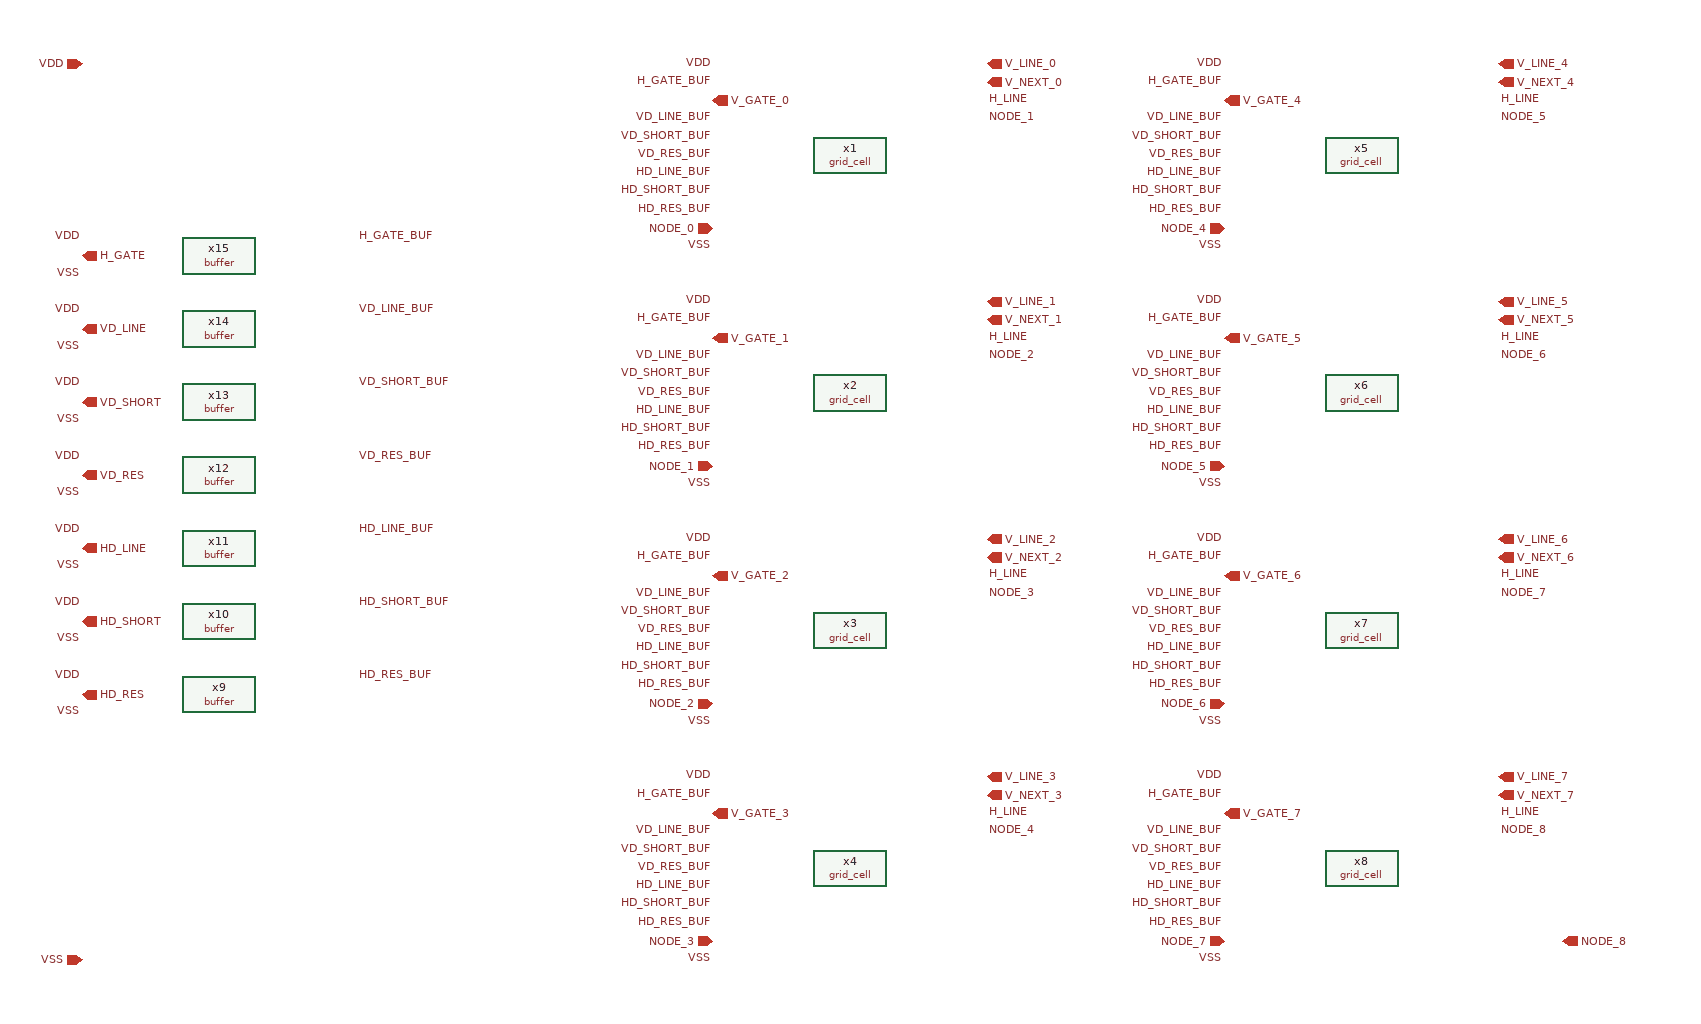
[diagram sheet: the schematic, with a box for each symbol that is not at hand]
v {xschem version=3.4.5 file_version=1.2
}
G {}
K {}
V {}
S {}
E {}
C {grid_cell.sym} 1120 -1040 0 0 {name=x1}
C {devices/lab_pin.sym} 970 -940 0 0 {name=p1 sig_type=std_logic lab=VSS}
C {devices/lab_pin.sym} 970 -1140 0 0 {name=p2 sig_type=std_logic lab=VDD}
C {devices/iopin.sym} 280 -160 2 0 {name=p7 lab=VSS}
C {devices/iopin.sym} 280 -1140 2 0 {name=p3 lab=VDD}
C {devices/iopin.sym} 970 -960 2 0 {name=p4 lab=NODE_0}
C {devices/ipin.sym} 280 -450 2 1 {name=p5 lab=HD_RES}
C {devices/ipin.sym} 280 -530 2 1 {name=p6 lab=HD_SHORT}
C {devices/ipin.sym} 280 -610 2 1 {name=p8 lab=HD_LINE}
C {buffer.sym} 430 -450 0 0 {name=x9}
C {buffer.sym} 430 -530 0 0 {name=x10}
C {buffer.sym} 430 -610 0 0 {name=x11}
C {devices/lab_pin.sym} 280 -430 0 0 {name=p24 sig_type=std_logic lab=VSS}
C {devices/lab_pin.sym} 280 -510 0 0 {name=p25 sig_type=std_logic lab=VSS}
C {devices/lab_pin.sym} 280 -590 0 0 {name=p26 sig_type=std_logic lab=VSS}
C {devices/lab_pin.sym} 280 -470 0 0 {name=p28 sig_type=std_logic lab=VDD}
C {devices/lab_pin.sym} 280 -550 0 0 {name=p29 sig_type=std_logic lab=VDD}
C {devices/lab_pin.sym} 280 -630 0 0 {name=p30 sig_type=std_logic lab=VDD}
C {devices/lab_pin.sym} 970 -980 0 0 {name=p36 sig_type=std_logic lab=HD_RES_BUF}
C {devices/lab_pin.sym} 970 -1000 0 0 {name=p37 sig_type=std_logic lab=HD_SHORT_BUF}
C {devices/lab_pin.sym} 970 -1020 0 0 {name=p38 sig_type=std_logic lab=HD_LINE_BUF}
C {devices/ipin.sym} 970 -1100 2 1 {name=p41 lab=V_GATE_0}
C {devices/lab_pin.sym} 970 -1120 0 0 {name=p42 sig_type=std_logic lab=H_GATE_BUF}
C {devices/iopin.sym} 1270 -1140 2 1 {name=p43 lab=V_LINE_0}
C {devices/iopin.sym} 1270 -1120 2 1 {name=p44 lab=V_NEXT_0}
C {devices/lab_pin.sym} 1270 -1100 0 1 {name=p45 sig_type=std_logic lab=H_LINE}
C {devices/lab_pin.sym} 1270 -1080 0 1 {name=p46 sig_type=std_logic lab=NODE_1}
C {grid_cell.sym} 1120 -780 0 0 {name=x2}
C {devices/lab_pin.sym} 970 -680 0 0 {name=p10 sig_type=std_logic lab=VSS}
C {devices/lab_pin.sym} 970 -880 0 0 {name=p11 sig_type=std_logic lab=VDD}
C {devices/lab_pin.sym} 970 -720 0 0 {name=p14 sig_type=std_logic lab=HD_RES_BUF}
C {devices/lab_pin.sym} 970 -740 0 0 {name=p15 sig_type=std_logic lab=HD_SHORT_BUF}
C {devices/lab_pin.sym} 970 -760 0 0 {name=p16 sig_type=std_logic lab=HD_LINE_BUF}
C {devices/ipin.sym} 970 -840 2 1 {name=p19 lab=V_GATE_1}
C {devices/lab_pin.sym} 970 -860 0 0 {name=p20 sig_type=std_logic lab=H_GATE_BUF}
C {devices/iopin.sym} 1270 -880 2 1 {name=p21 lab=V_LINE_1}
C {devices/iopin.sym} 1270 -860 2 1 {name=p22 lab=V_NEXT_1}
C {devices/lab_pin.sym} 1270 -840 0 1 {name=p23 sig_type=std_logic lab=H_LINE}
C {devices/lab_pin.sym} 1270 -820 0 1 {name=p33 sig_type=std_logic lab=NODE_2}
C {grid_cell.sym} 1120 -520 0 0 {name=x3}
C {devices/lab_pin.sym} 970 -420 0 0 {name=p34 sig_type=std_logic lab=VSS}
C {devices/lab_pin.sym} 970 -620 0 0 {name=p47 sig_type=std_logic lab=VDD}
C {devices/lab_pin.sym} 970 -460 0 0 {name=p50 sig_type=std_logic lab=HD_RES_BUF}
C {devices/lab_pin.sym} 970 -480 0 0 {name=p51 sig_type=std_logic lab=HD_SHORT_BUF}
C {devices/lab_pin.sym} 970 -500 0 0 {name=p52 sig_type=std_logic lab=HD_LINE_BUF}
C {devices/ipin.sym} 970 -580 2 1 {name=p55 lab=V_GATE_2}
C {devices/lab_pin.sym} 970 -600 0 0 {name=p56 sig_type=std_logic lab=H_GATE_BUF}
C {devices/iopin.sym} 1270 -620 2 1 {name=p57 lab=V_LINE_2}
C {devices/iopin.sym} 1270 -600 2 1 {name=p58 lab=V_NEXT_2}
C {devices/lab_pin.sym} 1270 -580 0 1 {name=p59 sig_type=std_logic lab=H_LINE}
C {devices/lab_pin.sym} 1270 -560 0 1 {name=p60 sig_type=std_logic lab=NODE_3}
C {grid_cell.sym} 1120 -260 0 0 {name=x4}
C {devices/lab_pin.sym} 970 -160 0 0 {name=p61 sig_type=std_logic lab=VSS}
C {devices/lab_pin.sym} 970 -360 0 0 {name=p62 sig_type=std_logic lab=VDD}
C {devices/lab_pin.sym} 970 -200 0 0 {name=p65 sig_type=std_logic lab=HD_RES_BUF}
C {devices/lab_pin.sym} 970 -220 0 0 {name=p66 sig_type=std_logic lab=HD_SHORT_BUF}
C {devices/lab_pin.sym} 970 -240 0 0 {name=p67 sig_type=std_logic lab=HD_LINE_BUF}
C {devices/ipin.sym} 970 -320 2 1 {name=p70 lab=V_GATE_3}
C {devices/lab_pin.sym} 970 -340 0 0 {name=p71 sig_type=std_logic lab=H_GATE_BUF}
C {devices/iopin.sym} 1270 -360 2 1 {name=p72 lab=V_LINE_3}
C {devices/iopin.sym} 1270 -340 2 1 {name=p73 lab=V_NEXT_3}
C {devices/lab_pin.sym} 1270 -320 0 1 {name=p74 sig_type=std_logic lab=H_LINE}
C {devices/lab_pin.sym} 1270 -300 0 1 {name=p75 sig_type=std_logic lab=NODE_4}
C {grid_cell.sym} 1680 -1040 0 0 {name=x5}
C {devices/lab_pin.sym} 1530 -940 0 0 {name=p76 sig_type=std_logic lab=VSS}
C {devices/lab_pin.sym} 1530 -1140 0 0 {name=p77 sig_type=std_logic lab=VDD}
C {devices/lab_pin.sym} 1530 -980 0 0 {name=p80 sig_type=std_logic lab=HD_RES_BUF}
C {devices/lab_pin.sym} 1530 -1000 0 0 {name=p81 sig_type=std_logic lab=HD_SHORT_BUF}
C {devices/lab_pin.sym} 1530 -1020 0 0 {name=p82 sig_type=std_logic lab=HD_LINE_BUF}
C {devices/ipin.sym} 1530 -1100 2 1 {name=p85 lab=V_GATE_4}
C {devices/lab_pin.sym} 1530 -1120 0 0 {name=p86 sig_type=std_logic lab=H_GATE_BUF}
C {devices/iopin.sym} 1830 -1140 2 1 {name=p87 lab=V_LINE_4}
C {devices/iopin.sym} 1830 -1120 2 1 {name=p88 lab=V_NEXT_4}
C {devices/lab_pin.sym} 1830 -1100 0 1 {name=p89 sig_type=std_logic lab=H_LINE}
C {devices/lab_pin.sym} 1830 -1080 0 1 {name=p90 sig_type=std_logic lab=NODE_5}
C {grid_cell.sym} 1680 -780 0 0 {name=x6}
C {devices/lab_pin.sym} 1530 -680 0 0 {name=p91 sig_type=std_logic lab=VSS}
C {devices/lab_pin.sym} 1530 -880 0 0 {name=p92 sig_type=std_logic lab=VDD}
C {devices/lab_pin.sym} 1530 -720 0 0 {name=p95 sig_type=std_logic lab=HD_RES_BUF}
C {devices/lab_pin.sym} 1530 -740 0 0 {name=p96 sig_type=std_logic lab=HD_SHORT_BUF}
C {devices/lab_pin.sym} 1530 -760 0 0 {name=p97 sig_type=std_logic lab=HD_LINE_BUF}
C {devices/ipin.sym} 1530 -840 2 1 {name=p100 lab=V_GATE_5}
C {devices/lab_pin.sym} 1530 -860 0 0 {name=p101 sig_type=std_logic lab=H_GATE_BUF}
C {devices/iopin.sym} 1830 -880 2 1 {name=p102 lab=V_LINE_5}
C {devices/iopin.sym} 1830 -860 2 1 {name=p103 lab=V_NEXT_5}
C {devices/lab_pin.sym} 1830 -840 0 1 {name=p104 sig_type=std_logic lab=H_LINE}
C {devices/lab_pin.sym} 1830 -820 0 1 {name=p105 sig_type=std_logic lab=NODE_6}
C {grid_cell.sym} 1680 -520 0 0 {name=x7}
C {devices/lab_pin.sym} 1530 -420 0 0 {name=p106 sig_type=std_logic lab=VSS}
C {devices/lab_pin.sym} 1530 -620 0 0 {name=p107 sig_type=std_logic lab=VDD}
C {devices/lab_pin.sym} 1530 -460 0 0 {name=p110 sig_type=std_logic lab=HD_RES_BUF}
C {devices/lab_pin.sym} 1530 -480 0 0 {name=p111 sig_type=std_logic lab=HD_SHORT_BUF}
C {devices/lab_pin.sym} 1530 -500 0 0 {name=p112 sig_type=std_logic lab=HD_LINE_BUF}
C {devices/ipin.sym} 1530 -580 2 1 {name=p115 lab=V_GATE_6}
C {devices/lab_pin.sym} 1530 -600 0 0 {name=p116 sig_type=std_logic lab=H_GATE_BUF}
C {devices/iopin.sym} 1830 -620 2 1 {name=p117 lab=V_LINE_6}
C {devices/iopin.sym} 1830 -600 2 1 {name=p118 lab=V_NEXT_6}
C {devices/lab_pin.sym} 1830 -580 0 1 {name=p119 sig_type=std_logic lab=H_LINE}
C {devices/lab_pin.sym} 1830 -560 0 1 {name=p120 sig_type=std_logic lab=NODE_7}
C {grid_cell.sym} 1680 -260 0 0 {name=x8}
C {devices/lab_pin.sym} 1530 -160 0 0 {name=p121 sig_type=std_logic lab=VSS}
C {devices/lab_pin.sym} 1530 -360 0 0 {name=p122 sig_type=std_logic lab=VDD}
C {devices/lab_pin.sym} 1530 -200 0 0 {name=p125 sig_type=std_logic lab=HD_RES_BUF}
C {devices/lab_pin.sym} 1530 -220 0 0 {name=p126 sig_type=std_logic lab=HD_SHORT_BUF}
C {devices/lab_pin.sym} 1530 -240 0 0 {name=p127 sig_type=std_logic lab=HD_LINE_BUF}
C {devices/ipin.sym} 1530 -320 2 1 {name=p130 lab=V_GATE_7}
C {devices/lab_pin.sym} 1530 -340 0 0 {name=p131 sig_type=std_logic lab=H_GATE_BUF}
C {devices/iopin.sym} 1830 -360 2 1 {name=p132 lab=V_LINE_7}
C {devices/iopin.sym} 1830 -340 2 1 {name=p133 lab=V_NEXT_7}
C {devices/lab_pin.sym} 1830 -320 0 1 {name=p134 sig_type=std_logic lab=H_LINE}
C {devices/lab_pin.sym} 1830 -300 0 1 {name=p135 sig_type=std_logic lab=NODE_8}
C {devices/lab_pin.sym} 580 -630 0 1 {name=p137 sig_type=std_logic lab=HD_LINE_BUF}
C {devices/lab_pin.sym} 580 -550 0 1 {name=p138 sig_type=std_logic lab=HD_SHORT_BUF}
C {devices/lab_pin.sym} 580 -470 0 1 {name=p139 sig_type=std_logic lab=HD_RES_BUF}
C {devices/iopin.sym} 1900 -180 2 1 {name=p140 lab=NODE_8}
C {devices/iopin.sym} 970 -700 2 0 {name=p13 lab=NODE_1}
C {devices/iopin.sym} 970 -440 2 0 {name=p35 lab=NODE_2}
C {devices/iopin.sym} 970 -180 2 0 {name=p49 lab=NODE_3}
C {devices/iopin.sym} 1530 -960 2 0 {name=p64 lab=NODE_4}
C {devices/iopin.sym} 1530 -700 2 0 {name=p79 lab=NODE_5}
C {devices/iopin.sym} 1530 -440 2 0 {name=p94 lab=NODE_6}
C {devices/iopin.sym} 1530 -180 2 0 {name=p109 lab=NODE_7}
C {devices/ipin.sym} 280 -690 2 1 {name=p9 lab=VD_RES}
C {devices/ipin.sym} 280 -770 2 1 {name=p27 lab=VD_SHORT}
C {devices/ipin.sym} 280 -850 2 1 {name=p31 lab=VD_LINE}
C {buffer.sym} 430 -690 0 0 {name=x12}
C {buffer.sym} 430 -770 0 0 {name=x13}
C {buffer.sym} 430 -850 0 0 {name=x14}
C {devices/lab_pin.sym} 280 -670 0 0 {name=p124 sig_type=std_logic lab=VSS}
C {devices/lab_pin.sym} 280 -750 0 0 {name=p136 sig_type=std_logic lab=VSS}
C {devices/lab_pin.sym} 280 -830 0 0 {name=p141 sig_type=std_logic lab=VSS}
C {devices/lab_pin.sym} 280 -710 0 0 {name=p142 sig_type=std_logic lab=VDD}
C {devices/lab_pin.sym} 280 -790 0 0 {name=p143 sig_type=std_logic lab=VDD}
C {devices/lab_pin.sym} 280 -870 0 0 {name=p144 sig_type=std_logic lab=VDD}
C {devices/lab_pin.sym} 580 -870 0 1 {name=p145 sig_type=std_logic lab=VD_LINE_BUF
}
C {devices/lab_pin.sym} 580 -790 0 1 {name=p146 sig_type=std_logic lab=VD_SHORT_BUF}
C {devices/lab_pin.sym} 580 -710 0 1 {name=p147 sig_type=std_logic lab=VD_RES_BUF}
C {devices/ipin.sym} 280 -930 2 1 {name=p148 lab=H_GATE}
C {buffer.sym} 430 -930 0 0 {name=x15}
C {devices/lab_pin.sym} 280 -910 0 0 {name=p149 sig_type=std_logic lab=VSS}
C {devices/lab_pin.sym} 280 -950 0 0 {name=p150 sig_type=std_logic lab=VDD}
C {devices/lab_pin.sym} 580 -950 0 1 {name=p151 sig_type=std_logic lab=H_GATE_BUF}
C {devices/lab_pin.sym} 970 -1080 0 0 {name=p12 sig_type=std_logic lab=VD_LINE_BUF
}
C {devices/lab_pin.sym} 970 -1060 0 0 {name=p17 sig_type=std_logic lab=VD_SHORT_BUF}
C {devices/lab_pin.sym} 970 -1040 0 0 {name=p18 sig_type=std_logic lab=VD_RES_BUF}
C {devices/lab_pin.sym} 970 -820 0 0 {name=p32 sig_type=std_logic lab=VD_LINE_BUF
}
C {devices/lab_pin.sym} 970 -800 0 0 {name=p39 sig_type=std_logic lab=VD_SHORT_BUF}
C {devices/lab_pin.sym} 970 -780 0 0 {name=p40 sig_type=std_logic lab=VD_RES_BUF}
C {devices/lab_pin.sym} 970 -560 0 0 {name=p48 sig_type=std_logic lab=VD_LINE_BUF
}
C {devices/lab_pin.sym} 970 -540 0 0 {name=p53 sig_type=std_logic lab=VD_SHORT_BUF}
C {devices/lab_pin.sym} 970 -520 0 0 {name=p54 sig_type=std_logic lab=VD_RES_BUF}
C {devices/lab_pin.sym} 970 -300 0 0 {name=p63 sig_type=std_logic lab=VD_LINE_BUF
}
C {devices/lab_pin.sym} 970 -280 0 0 {name=p68 sig_type=std_logic lab=VD_SHORT_BUF}
C {devices/lab_pin.sym} 970 -260 0 0 {name=p69 sig_type=std_logic lab=VD_RES_BUF}
C {devices/lab_pin.sym} 1530 -1080 0 0 {name=p78 sig_type=std_logic lab=VD_LINE_BUF
}
C {devices/lab_pin.sym} 1530 -1060 0 0 {name=p83 sig_type=std_logic lab=VD_SHORT_BUF}
C {devices/lab_pin.sym} 1530 -1040 0 0 {name=p84 sig_type=std_logic lab=VD_RES_BUF}
C {devices/lab_pin.sym} 1530 -820 0 0 {name=p93 sig_type=std_logic lab=VD_LINE_BUF
}
C {devices/lab_pin.sym} 1530 -800 0 0 {name=p98 sig_type=std_logic lab=VD_SHORT_BUF}
C {devices/lab_pin.sym} 1530 -780 0 0 {name=p99 sig_type=std_logic lab=VD_RES_BUF}
C {devices/lab_pin.sym} 1530 -560 0 0 {name=p108 sig_type=std_logic lab=VD_LINE_BUF
}
C {devices/lab_pin.sym} 1530 -540 0 0 {name=p113 sig_type=std_logic lab=VD_SHORT_BUF}
C {devices/lab_pin.sym} 1530 -520 0 0 {name=p114 sig_type=std_logic lab=VD_RES_BUF}
C {devices/lab_pin.sym} 1530 -300 0 0 {name=p123 sig_type=std_logic lab=VD_LINE_BUF
}
C {devices/lab_pin.sym} 1530 -280 0 0 {name=p128 sig_type=std_logic lab=VD_SHORT_BUF}
C {devices/lab_pin.sym} 1530 -260 0 0 {name=p129 sig_type=std_logic lab=VD_RES_BUF}
